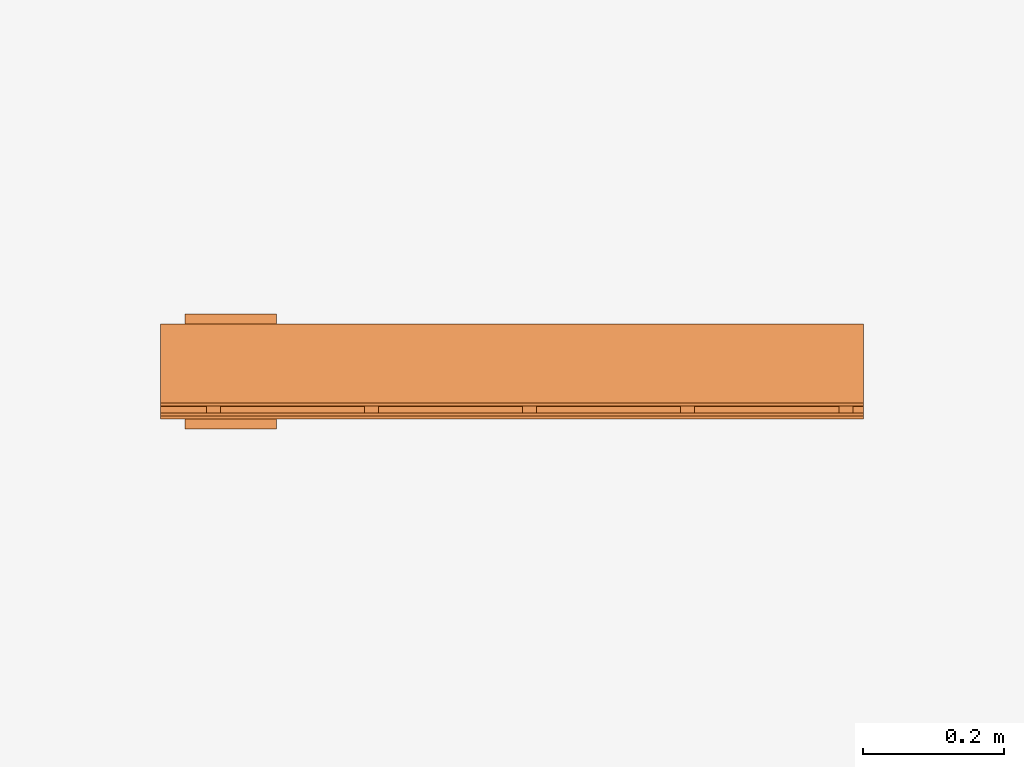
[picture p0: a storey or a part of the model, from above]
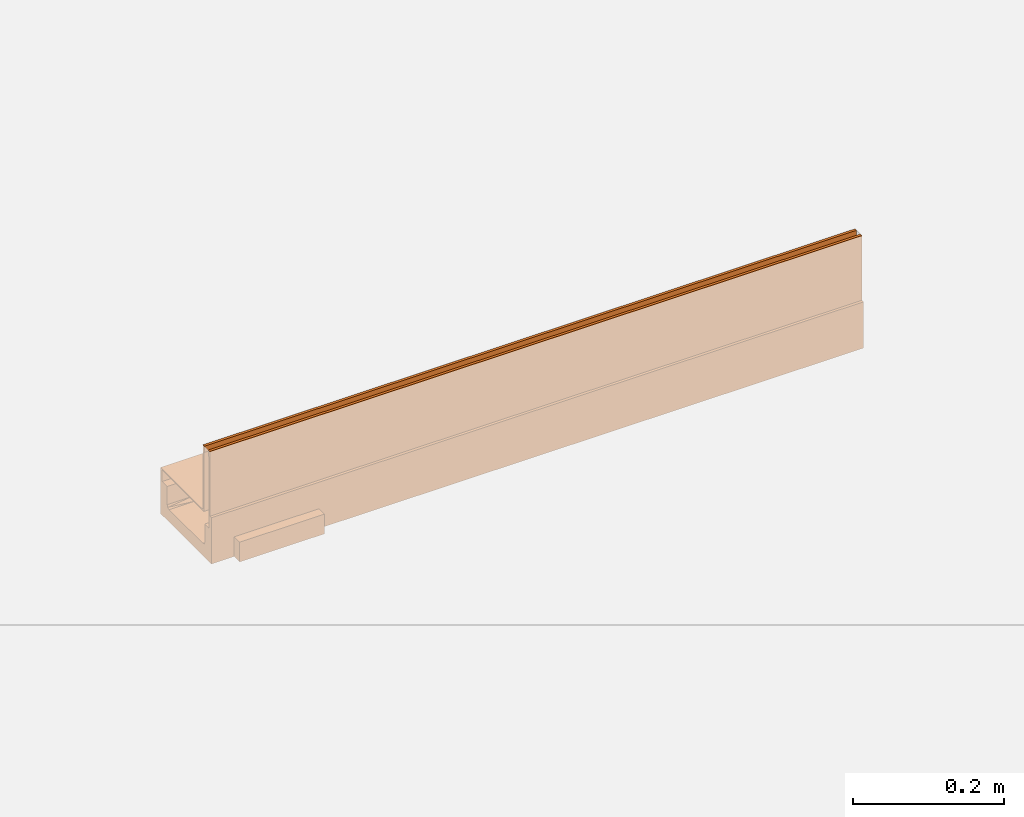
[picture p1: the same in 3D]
Properties of the parts of a building model (IFC2X3)

# File
Description: ViewDefinition [CoordinationView]
Time: 2013-10-31T17:31:22
Written by: Autodesk Revit 2013
Made in: 20120221_2030(x64)

# IfcProject, Project Number
LongName: Project Name; Phase: Project Status

# IfcSite, Default
RefLatitude: 42, 21, 30, 344238; RefLongitude: -71, -3, -35, -194702; RefElevation: 0 mm

# IfcBuilding
Pset_BuildingCommon - NumberOfStoreys: 1
Other - Project Name: Project Name; Project Number: Project Number; Project Issue Date: Issue Date; Project Address: ## Street City, State Zip; Project Status: Project Status; Client Name: Owner

# IfcBuildingStorey, Level 1
LongName: Level 1; Elevation: 0 mm
Constraints - Elevation Base: 0; Elevation: 0 mm
Graphics - Line Pattern: Center; Symbol at End 1 Default: no; Line Weight: 1; Symbol at End 2 Default: yes; Symbol: M_Level Head - Circle: M_Level Head - Circle; Color: 0
Identity Data - Building Story: yes; Name: Level 1; Structural: no
Dimensions - Computation Height: 0 mm

# IfcBuildingElementProxy: 23076 - No 075V Constant Depth Outlet Shallow Channel - 1000mm LG – Invert Depth 55mm, Civil-Drainage-Channel-ACO-MultiDrain-M100D-Brickslot-Channel-System:23076 - No 075V Constant Depth Outlet Shallow Channel - 1000mm LG – Invert Depth 55mm:23076 - No 075V Constant Depth Outlet Shallow Channel - 1000mm LG – Invert Depth 55mm:196059
In: Level 1
Material: Steel, Galvanized, Plastic, Opaque Black, Vienite® Synthetic Resin Concrete
Dimensions - Brickslot Access Unit Void Depth: -6500 mm; Custom_Void_length: 0 mm; Length: 1000 mm; Brickslot Access Unit Void Bottom Depth: -6605 mm; Brickslot Void Length: 1000 mm; Volume: 4830976 mm3; FloorCut_Length: -1000 mm; Brickslot Void Depth: 0 mm; EndCap Position: 1000 mm; ShallowInvDepth: 55 mm; SlopingEndOverallDepth: 250 mm; FloorCut_Depth: 75 mm; Brickslot Access Unit Floor Cut Length: 500 mm; Length Drain: -1000 mm; ShallowOverallDepth: 75 mm; SlopingInvertDepth: 175 mm; SlopingEndInvertDepth: 180 mm; Access_Custom_Void_Length: 0 mm; InvDepth: 80 mm; FloorCut_Width: 135 mm; GratingLength: -1000 mm; EndCap_Height: 75 mm; Depth: 150 mm; SlopingOverallDepth: 245 mm; Floor Cut Gap: 105 mm
Construction - 23462_Load Class C250_Brickslot Access Unit_Galvanised Steel_500mm Long: no; 23460_Load Class C250_Brickslot Grating_Galvanized Steel_1000mm Long: no; 23404_Universal Endcap (Male End): no; 23466_Load Class D400_Brickslot Grating_Galvanized Steel_500mm Long: no; 23461_Load Class C250_Brickslot Grating_Galvanized Steel_500mm Long: no; 23467_Load Class D400_Brickslot Access Unit_Galvanised Steel_500mm Long: no; 23465_Load Class D400_Brickslot Grating_Galvanized Steel_1000mm Long: yes; 23404_Universal Endcap (Female End): no; Sloping Channel: no; Constant Depth Junction Channel: no; Constant Depth Channel: no; Shallow Depth Channel with seal: yes; 23410_Sump Unit: no; Shallow Depth Channel: no
Constraints - Level: Level: Level 1; Moves With Nearby Elements: no
Phasing - Phase Created: New Construction
Pset_BuildingElementProxyCommon - Reference: 23076 - No 075V Constant Depth Outlet Shallow Channel - 1000mm LG – Invert Depth 55mm
General - TagNumber: 0; SerialNumber: 0
Materials and Finishes - Edge Rail Finish: Pre-galvanised; Channel Colour: Brown; Edge Rail Material: Steel; Edge Rail Colour: Silver; Channel Material: Vienite® Synthetic Resin Concrete
Data - Product Weight: 8.85 Kg; Concrete Surround Volume - Load Class A 15 - Concrete Pavement: 0.05m³/m; Concrete Surround Volume - Load Class B 125 - C 250 - Concrete Pavement: 0.09m³/m; Invert Depth: 55mm; Product Standard: BS EN 1433:2002, CE marked 0.0034m² 55mm; Hydraulic Performance: http://www.aco.co.uk/download.php?id=173; Concrete Surround Volume - Load Class D 400 - Concrete Pavement: 0.14m³/m 0.14m³/m; ACO Hydraulic Design Software: http://www.acodesign.co.uk; Product Dimensions: 1000mm x 135mm x 75mm (LxWxH); Pre-formed Outlet Ø: 110mm; Load Class: A 15 - D 400; Installation - Concrete Grade: Refer to brochure; Channel C.S.A: 0.0034m²
Identity Data - Type Comments: ACO MultiDrain M100D No 075V Constant Depth Shallow Outlet Channel 1000mm Long; Manufacturer: ACO Technologies plc - ACO Water Management Division; Assembly Code: D2040; OmniClass Title: Rainwater Removal; Installation guidelines: http://www.aco.co.uk/download.php?id=173; Watermarked With: BIM Manager Premium Suite; Product Code: 23076; Model Description: Channel drainage system; Assembly Description: Rain Water Drainage; Watermark 2: This file is water marked and users are prohibited to reproduce, adapt, distribute this information; Product Page URL: http://www.aco.co.uk/product_detail.php?id=58; Watermark 1: This file is the property of ACO Technologies PLC; OmniClass Number: 23.70.50.24; Telephone: +44 (0)1462 816666; Fax: +44 (0)1462 815895; URL: www.aco.co.uk; Cost: 0; Model: ACO MultiDrain MD Brickslot- M100D; e-mail Technical: technical@aco.co.uk; e-mail Sales: customersupport@aco.co.uk; Product brochure: http://www.aco.co.uk/download.php?id=173; Price: POA - contact ACO; Maintenance guidelines: http://www.aco.co.uk/download.php?id=173; Address: ACO Business Park, Hitchin Road, Shefford, Bedfordshire, United Kingdom SG17 5TE
Other - Revision: 1; Created By: www.aco.co.uk; Watermarked By: www.aco.co.uk
Model Properties - Brickslot Access Unit Product code 23467: Load Class D400 - Brickslot Access Unit Galvanised Steel - 500mm long x 105mm high - 10mm Slot - Intake area - 10000mm²/m - 6.4 Kg; Brickslot Grating Product code 23461: Load Class C250 - Brickslot Galvanised Steel - 500mm long x 105mm high - 10mm Slot - Intake area - 10000mm²/m -3.3 Kg; Brickslot Access Unit Product code 23462: Load Class C250 - Brickslot Access Unit Galvanised Steel - 500mm long x 105mm high - 10mm Slot - Intake area - 10000mm²/m - 6.4 Kg; Brickslot Grating Product code 23460: Load Class C250 - Brickslot Galvanised Steel - 1000mm long x 105mm high - 10mm Slot - Intake area - 10000mm²/m - 6.6 Kg; Brickslot Grating Product code 23466: Load Class D400 - Brickslot Galvanised Steel - 500mm long x 105mm high - 10mm Slot - Intake area - 10000mm²/m - 3.3 Kg; End Cap Product code 23404: No 306 Universal End Cap - 135mm wide x 300mm long - Spigot Ø110mm x 50mm long - Silver - Polypropylene - 0.16kg; Brickslot Grating Product code 23465: Load Class D400 - Brickslot Galvanised Steel - 1000mm long x 105mm high - 10mm Slot - Intake area - 10000mm²/m - 6.6 Kg
Green Building Properties - Channel Recycled Material Content: 20% minimum; Edge Rail Recyclable: Fully recyclable; Channel Recyclable: Fully recyclable; Edge Rail Recycled Material Content: Between 40% - 90%

# IfcOpeningElement: Recess (2)
In: Level 1
Dimensions - Thickness: 1000 mm; Volume: 24987985000 mm3; Area: 25000000 mm2; Perimeter: 20000 mm
Constraints - Room Bounding: yes; Height Offset From Level: 0 mm; Related to Mass: no; Level: Level: Level 1
Phasing - Phase Created: New Construction
Structural - Structural: no; Enable Analytical Model: no
Analytical Properties - Absorptance: 0.1; Heat Transfer Coefficient (U): 0.837; Roughness: 1; Thermal Resistance (R): 1.19474; Thermal mass: 1359800
Construction - Function: 0; Default Thickness: 1000 mm
Graphics - Coarse Scale Fill Color: 0
Materials and Finishes - Structural Material: Earth

# IfcSlab: Floor:Generic Floor - 1000mm, Floor:Generic Floor - 1000mm:193825
In: Level 1
PredefinedType: FLOOR; Material: Earth 1000 mm
Dimensions - Thickness: 1000 mm; Volume: 24987985000 mm3; Area: 25000000 mm2; Perimeter: 20000 mm
Constraints - Room Bounding: yes; Height Offset From Level: 0 mm; Related to Mass: no; Level: Level: Level 1
Phasing - Phase Created: New Construction
Structural - Structural: no; Enable Analytical Model: no
Pset_SlabCommon - Reference: Generic Floor - 1000mm; IsExternal: no; LoadBearing: yes
Analytical Properties - Absorptance: 0.1; Heat Transfer Coefficient (U): 0.837; Roughness: 1; Thermal Resistance (R): 1.19474; Thermal mass: 1359800
Construction - Function: 0; Default Thickness: 1000 mm
Graphics - Coarse Scale Fill Color: 0
Materials and Finishes - Structural Material: Earth
